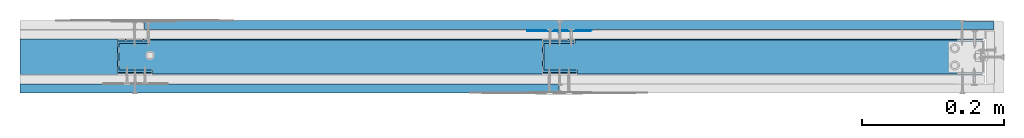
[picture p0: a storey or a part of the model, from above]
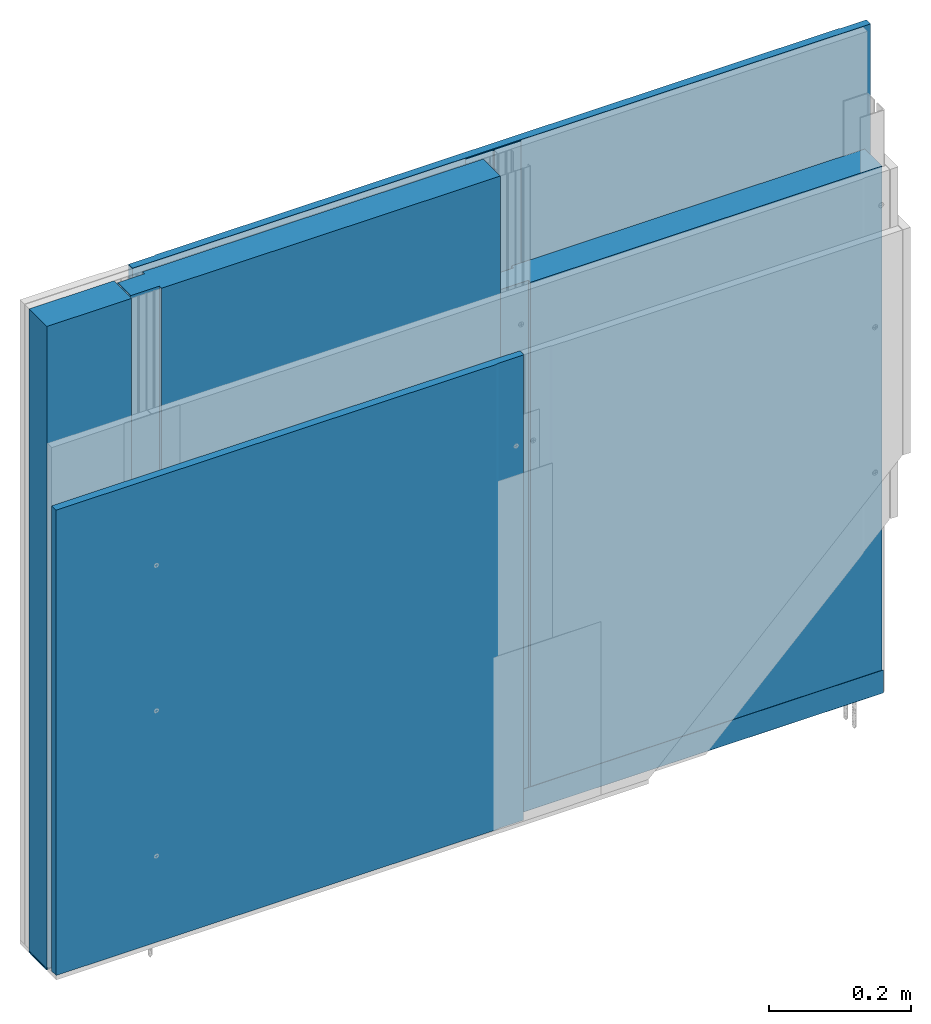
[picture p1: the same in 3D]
Properties of the parts of a building model (IFC2X3)

# File
Description: ViewDefinition [CoordinationView]
Time: 2022-01-04T16:14:53
Made in: SketchUp Pro 2015

# IfcProject, Default Project
Description: Description of Default Project

# IfcSite, Default Site
Description: Description of Default Site; RefLatitude: 24, 28, 0; RefLongitude: 54, 25, 0; RefElevation: 10 mm

# IfcBuilding, Default Building
Description: Description of Default Building

# IfcBuildingStorey, Default Building Storey
In: Default Building
Description: Description of Default Building Storey; Elevation: 0 mm

# IfcWall (82)
In: Default Building Storey
Description: Description of Object
Name
6 x Dedykowana masa szpachlowa Rigips - konstrukcyjna
2 x Taśma spoinowa RIGIPS
10 x Płyta gipsowo-kartonowa RIGIPS PRO (4PRO™)
12 x Wkręt RIGIPS TN 25
4 x Wkręt RIGIPS TB 25
13 x Wkręt RIGIPS TN 35
6 x Kołek rozporowy min. fi 6
3 x Wełna mineralna szklana lub skalna ISOVER
2 x Dedykowana masa szpachlowa Rigips - wykończeniowa
15 x Wkręt RIGIPS TB 35
Taśma uszczelniająca piankowa RIGIPS
Profil RIGIPS UW 50 ULTRASTIL®
2 x Profil RIGIPS CW50 ULTRASTIL®
Katownik RIGIPS do UA50 | TempShadowInfo - City: Boulder (CO); Country: USA; Latitude: 40.017; Longitude: 40.017-105.283; NorthAngle: 40.017-105.2830; TZOffset: 40.017-105.2830-7
Profil RIGIPS UA50 | TempShadowInfo - City: Boulder (CO); Country: USA; Latitude: 40.017; Longitude: 40.017-105.283; NorthAngle: 40.017-105.2830; TZOffset: 40.017-105.2830-7
Śruba M8 do profila UA z podkładką i nakrętką | TempShadowInfo - City: N/A; Country: N/A; Latitude: 358.49552.3674.9-2.4778e+07-2.28487e+08052.367; Longitude: 358.49552.3674.9-2.4778e+07-2.28487e+08052.3674.9; NorthAngle: 358.49552.3674.9-2.4778e+07-2.28487e+08052.3674.9358.495; TZOffset: 358.49552.3674.9-2.4778e+07-2.28487e+08052.3674.9358.4950; GeoReference - GeoReferenceNorthAngle: 358.495; Latitude: 358.49552.367; LocationSource: Google Earth; Longitude: 358.49552.3674.9; ModelTranslationX: 358.49552.3674.9-2.4778e+07; ModelTranslationY: 358.49552.3674.9-2.4778e+07-2.28487e+08; ModelTranslationZ: 358.49552.3674.9-2.4778e+07-2.28487e+080; 3DWarehouse - ModelID: 3ef38b8d7c02dae9c5ad3eca48dee261
2 x Śruba M8 do profila UA z podkładką i nakrętką | TempShadowInfo - City: Boulder (CO); Country: USA; Latitude: 0.15573140.0183-105.242-1.88715e+07-1.74402e+0840.0183; Longitude: 0.15573140.0183-105.242-1.88715e+07-1.74402e+0840.0183-105.242; NorthAngle: 0.15573140.0183-105.242-1.88715e+07-1.74402e+0840.0183-105.2420; TZOffset: 0.15573140.0183-105.242-1.88715e+07-1.74402e+0840.0183-105.2420-7; GeoReference - GeoReferenceNorthAngle: 0.155731; Latitude: 0.15573140.0183; LocationSource: Manual; Longitude: 0.15573140.0183-105.242; ModelTranslationX: 0.15573140.0183-105.242-1.88715e+07; ModelTranslationY: 0.15573140.0183-105.242-1.88715e+07-1.74402e+08
